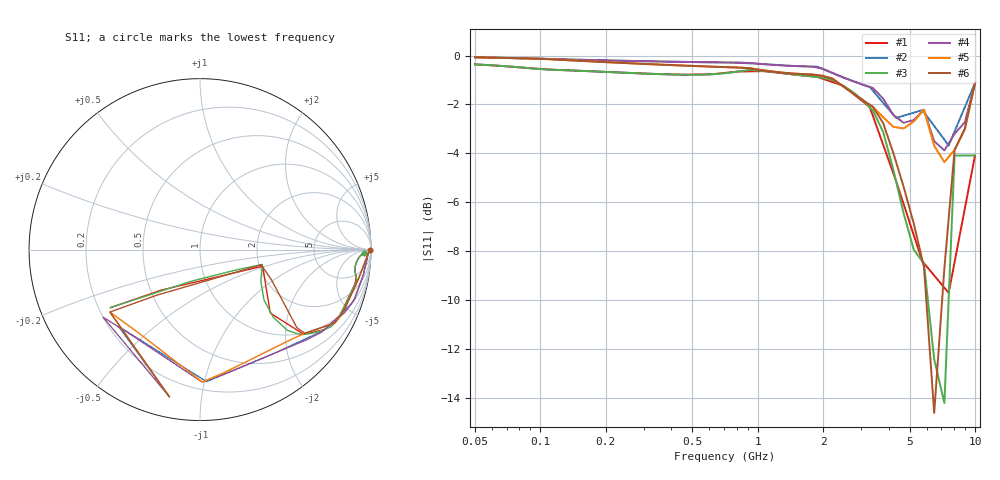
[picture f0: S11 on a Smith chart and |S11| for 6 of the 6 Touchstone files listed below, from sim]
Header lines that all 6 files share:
! AD8317 INHI/INLO input model, 0.05-10 GHz
! Sources: AD8317 Rev.D pp.3-4 impedance table + p.9 Figure 15 approximation
! INLO is RF common (AC-coupled to ground), modeled implicitly in single-ended S11 at INHI.
# GHZ S RI R 50
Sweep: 50 MHz to 10 GHz
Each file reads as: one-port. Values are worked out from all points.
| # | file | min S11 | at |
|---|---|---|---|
| 1 | AD8317_INHI_S11_20pt_0p05_to_10GHz.s1p | -9.7 dB | 7.566 GHz |
| 2 | AD8317_INHI_S11_20pt_0p05_to_10GHz_strict_smithfit.s1p | -3.7 dB | 7.566 GHz |
| 3 | AD8317_INHI_S11_50pt_0p05_to_10GHz.s1p | -14.2 dB | 7.23 GHz |
| 4 | AD8317_INHI_S11_50pt_0p05_to_10GHz_strict_smithfit.s1p | -3.9 dB | 7.23 GHz |
| 5 | AD8317_INHI_S11_50pt_combined_Gamma_at_5p8.s1p | -4.4 dB | 7.23 GHz |
| 6 | AD8317_INHI_S11_50pt_combined_RC_at_5p8.s1p | -14.6 dB | 6.489 GHz |
